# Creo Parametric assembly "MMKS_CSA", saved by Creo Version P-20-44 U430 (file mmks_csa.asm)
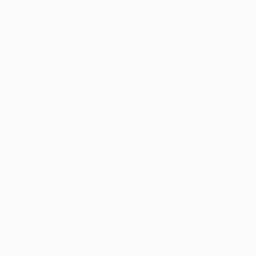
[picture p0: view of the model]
Units: millimeter Kilogram Sec (mmKs); MM, KILOGRAM, SECS

Created from: MMKS_ASM_DESIGN.ASM

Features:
  1. datum plane "ASM_RIGHT"
  2. datum plane "ASM_TOP"
  3. datum plane "ASM_FRONT"
  4. coordinate system

Other named items: CFSTR_MDL_CUR_CHOICE, CFSTR_MDL_CUR_SUBSET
